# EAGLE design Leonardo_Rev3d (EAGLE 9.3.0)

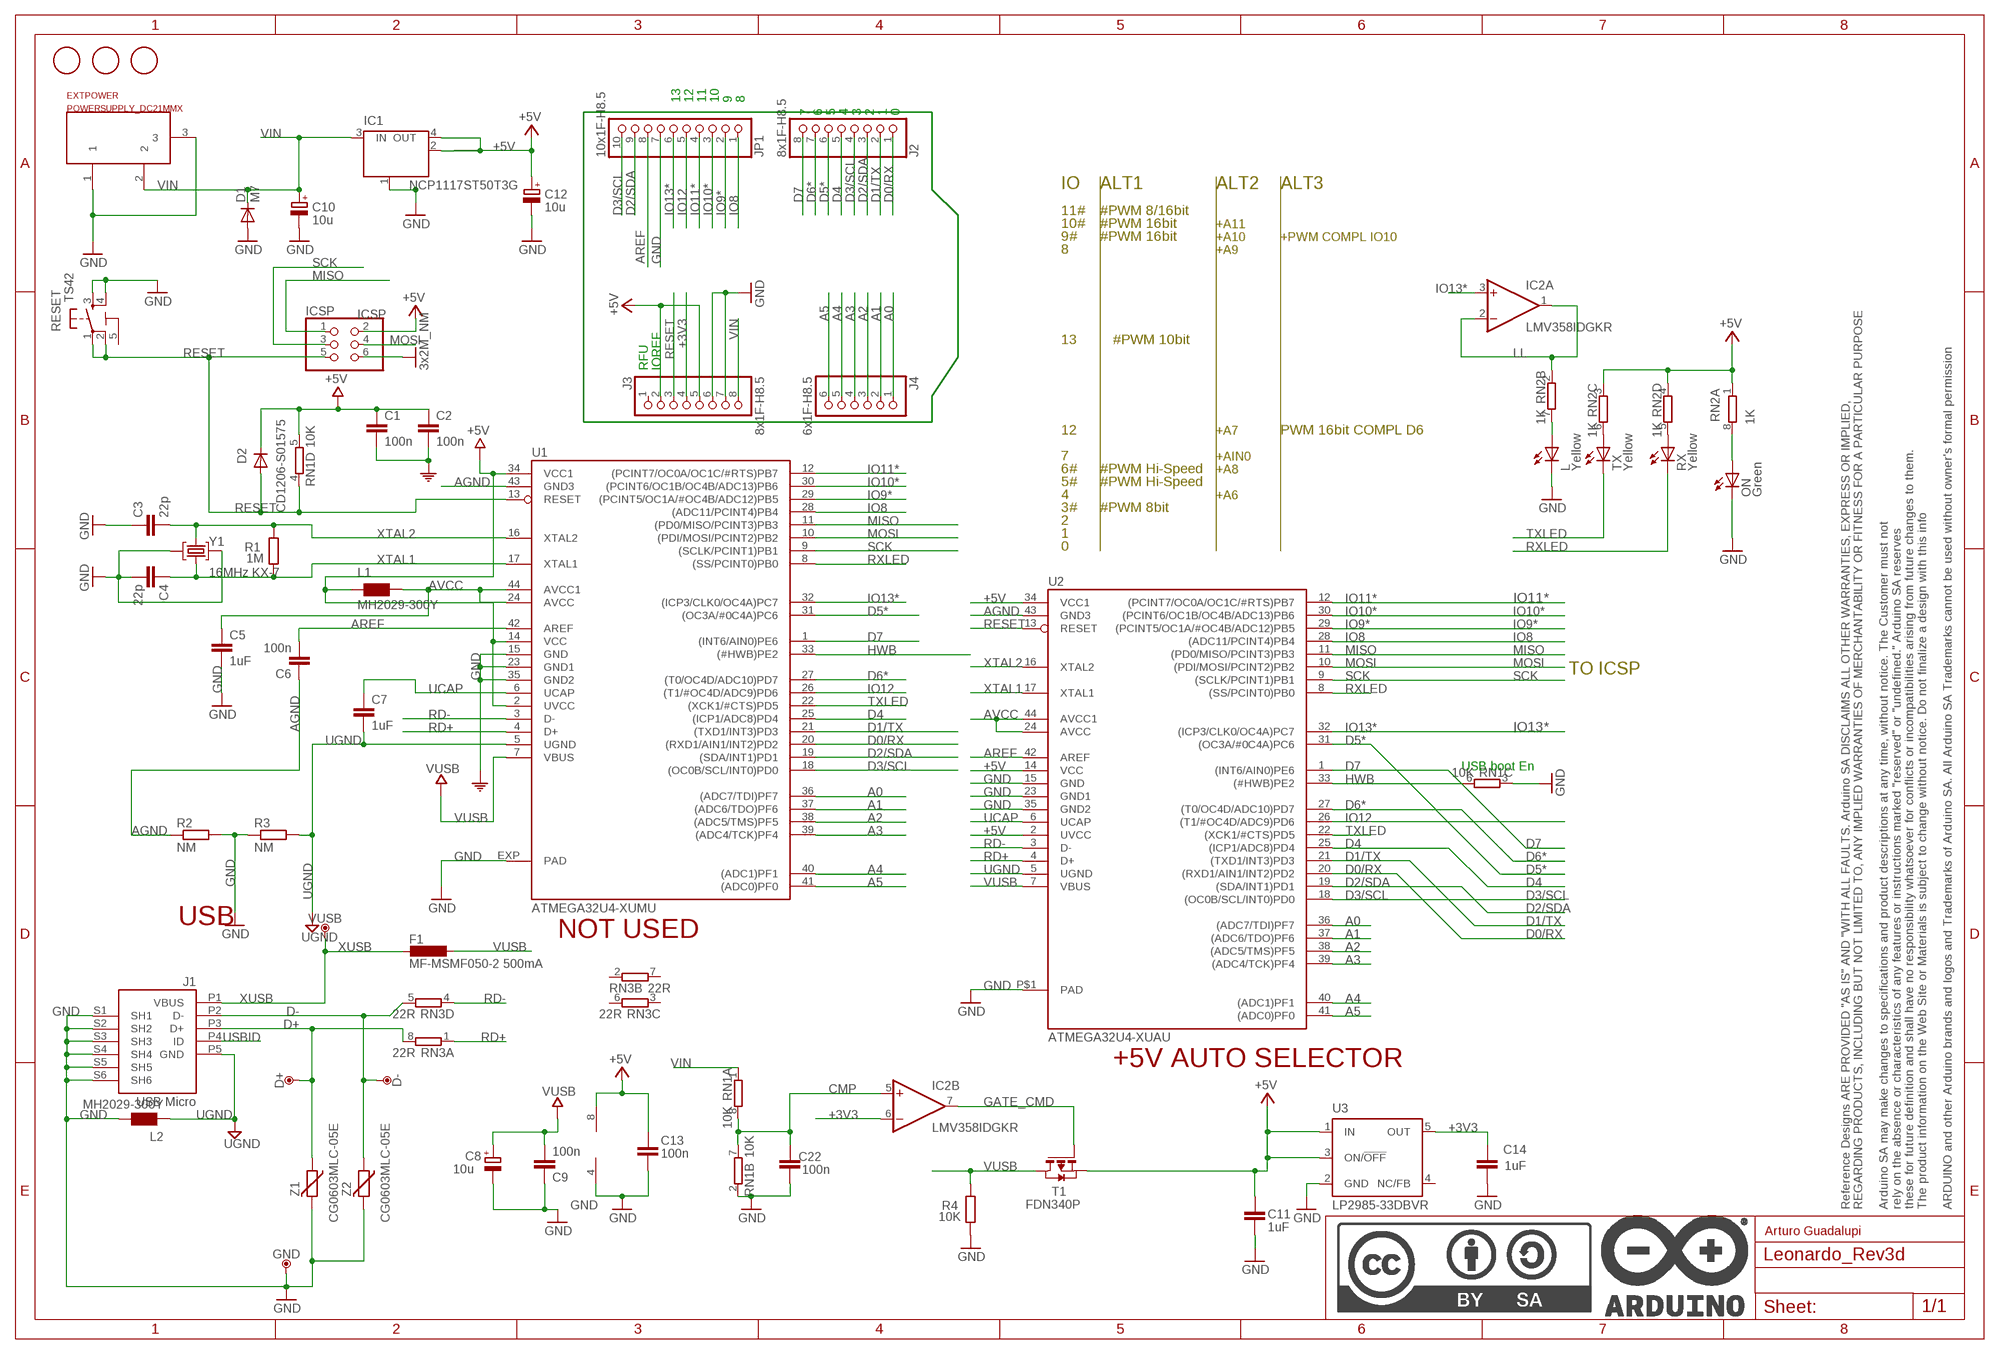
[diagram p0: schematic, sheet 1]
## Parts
C1  100n  C-EUC0603  [C0603-ROUND]
C2  100n  C-EUC0603  [C0603-ROUND]
C3  22p  C-EUC0603  [C0603-ROUND]
C4  22p  C-EUC0603  [C0603-ROUND]
C5  1uF  C-EUC0603  [C0603-ROUND]
C6  100n  C-EUC0603  [C0603-ROUND]
C7  1uF  C-EUC0603  [C0603-ROUND]
C8  10u  CPOL-EUSMCB  [SMC_B]
C9  100n  C-EUC0603  [C0603-ROUND]
C10  10u  CPOL-EUSMCB  [SMC_B]
C11  1uF  C-EUC0603  [C0603-ROUND]
C12  10u  CPOL-EUSMCB  [SMC_B]
C13  100n  C-EUC0603  [C0603-ROUND]
C14  1uF  C-EUC0603  [C0603-ROUND]
C22  100n  C-EUC0603  [C0603-ROUND]
D1  M7  DIODE-SMB  [SMB]
D2  CD1206-S01575  DIODE-MINIMELF  [MINIMELF]
D+  DNP  TPTP-1.00MM  [TP-1.00MM]
D-  DNP  TPTP-1.00MM  [TP-1.00MM]
EXTPOWER  POWERSUPPLY_DC21MMX  [POWERSUPPLY_DC-21MM]
F1  MF-MSMF050-2 500mA  L-EUL1812  [L1812]
FID1  DNP  FIDUCIAL-1.5MM  [FD-1-1.5]
FID2  DNP  FIDUCIAL-1.5MM  [FD-1-1.5]
FID3  DNP  FIDUCIAL-1.5MM  [FD-1-1.5]
FRAME1  DNP  A3-FRAME  [FRAME]
GND  DNP  TPTP-1.00MM  [TP-1.00MM]
IC1  NCP1117ST50T3G  MC33269ST-3.3T3  [SOT223]
IC2  LMV358IDGKR  LMV358MMX  [MSOP08]
ICSP  ICSP  PINHD-2X3  [2X03]
J1  USB Micro  USB-MICRO-LEGACY  [CON2_USB_MICRO_B_AT]
J2  8x1F-H8.5  PINHD-1X8  [1X08]
J3  8x1F-H8.5  PINHD-1X8  [1X08]
J4  6x1F-H8.5  PINHD-1X6  [1X06]
JP1  10x1F-H8.5  PINHD-1X10  [1X10]
L  Yellow  LEDCHIPLED_0805  [CHIPLED_0805]
L1  MH2029-300Y  WE-CBF_0805  [0805]
L2  MH2029-300Y  WE-CBF_0805  [0805]
ON  Green  LEDCHIPLED_0805  [CHIPLED_0805]
R1  1M  R-EU_R0603  [R0603-ROUND]
R2  NM  R-EU_R0402  [R0402]
R3  NM  R-EU_R0402  [R0402]
R4  10K  R-EU_R0603  [R0603-ROUND]
RESET  TS42  [TS42]
RN1  10K  4R-NCAY16  [CAY16]
RN2  1K  4R-NCAY16  [CAY16]
RN3  22R  4R-NCAY16  [CAY16]
RX  Yellow  LEDCHIPLED_0805  [CHIPLED_0805]
T1  FDN340P  PMOSSOT23  [SOT-23]
TX  Yellow  LEDCHIPLED_0805  [CHIPLED_0805]
U1  ATMEGA32U4-XUMU  [QFN44ML7X7]
U2  ATMEGA32U4-XUAU  [TQFP44-PAD]
U3  LP2985-33DBVR  LP2985-XXDBVR33  [SOT23-DBV]
VUSB  DNP  TPTP-1.00MM  [TP-1.00MM]
Y1  16MHz KX-7  CRYSTAL-3.2-2.5  [CRYSTAL-3.2-2.5]
Z1  CG0603MLC-05E  VARISTORCN0603  [CT/CN0603]
Z2  CG0603MLC-05E  VARISTORCN0603  [CT/CN0603]

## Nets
+3V3: C14.2 IC2.6(B:-IN) J3.4 U3.5(OUT)
+5V [usbvcc]: C1.1 C2.1 C11.2 C12.+ C13.1 D2.C IC1.2(OUT) IC1.4(OUT) IC2.8(P:V+) ICSP.2 J3.2 J3.5 L1.1 RN1.5 RN2.1 RN2.3 RN2.4 T1.2(S) U1.2(UVCC) U1.14(VCC) U1.34(VCC1) U2.2(UVCC) U2.14(VCC) U2.34(VCC1) U3.1(IN) U3.3(ON/!OFF)
A0: J4.1 U1.36((ADC7/TDI)PF7) U2.36((ADC7/TDI)PF7)
A1: J4.2 U1.37((ADC6/TDO)PF6) U2.37((ADC6/TDO)PF6)
A2: J4.3 U1.38((ADC5/TMS)PF5) U2.38((ADC5/TMS)PF5)
A3: J4.4 U1.39((ADC4/TCK)PF4) U2.39((ADC4/TCK)PF4)
A4: J4.5 U1.40((ADC1)PF1) U2.40((ADC1)PF1)
A5: J4.6 U1.41((ADC0)PF0) U2.41((ADC0)PF0)
AGND: C6.1 R2.1 U1.43(GND3) U2.43(GND3)
AREF [aref]: C6.2 JP1.8 U1.42(AREF) U2.42(AREF)
AVCC: C5.1 L1.2 U1.24(AVCC) U1.44(AVCC1) U2.24(AVCC) U2.44(AVCC1)
CMP: C22.2 IC2.5(B:+IN) RN1.7 RN1.8
D0/RX: J2.1 U1.20((RXD1/AIN1/INT2)PD2) U2.20((RXD1/AIN1/INT2)PD2)
D1/TX: J2.2 U1.21((TXD1/INT3)PD3) U2.21((TXD1/INT3)PD3)
D2/SDA: J2.3 JP1.9 U1.19((SDA/INT1)PD1) U2.19((SDA/INT1)PD1)
D3/SCL: J2.4 JP1.10 U1.18((OC0B/SCL/INT0)PD0) U2.18((OC0B/SCL/INT0)PD0)
D4: J2.5 U1.25((ICP1/ADC8)PD4) U2.25((ICP1/ADC8)PD4)
D5*: J2.6 U1.31((OC3A/#0C4A)PC6) U2.31((OC3A/#0C4A)PC6)
D6*: J2.7 U1.27((T0/OC4D/ADC10)PD7) U2.27((T0/OC4D/ADC10)PD7)
D7: J2.8 U1.1((INT6/AIN0)PE6) U2.1((INT6/AIN0)PE6)
D+: D+.X J1.P3(D+) RN3.8 Z1.1
D-: D-.X J1.P2(D-) RN3.5 Z2.1
GATE_CMD: IC2.7(B:OUT) T1.3(G)
GND [gnd]: C1.2 C2.2 C3.1 C4.2 C5.2 C8.- C9.1 C10.- C11.1 C12.- C13.2 C14.1 C22.1 D1.A EXTPOWER.1 EXTPOWER.3 GND.X IC1.1(GND/ADJ) IC2.4(P:V-) ICSP.6 J1.S1(SH1) J1.S2(SH2) J1.S3(SH3) J1.S4(SH4) J1.S5(SH5) J1.S6(SH6) J3.6 J3.7 JP1.7 L2.2 L.C ON.C R2.2 R3.1 R4.1 RESET.3 RESET.4 RN1.2 RN1.3 U1.15(GND) U1.23(GND1) U1.35(GND2) U1.EXP(PAD) U2.15(GND) U2.23(GND1) U2.35(GND2) U2.P$1(PAD) U3.2(GND) Y1.2(GND) Y1.4(GND) Z1.2 Z2.2 ; supply symbol labelled 3x2M_NM, COM
HWB: RN1.6 U1.33((#HWB)PE2) U2.33((#HWB)PE2)
IO8: JP1.1 U1.28((ADC11/PCINT4)PB4) U2.28((ADC11/PCINT4)PB4)
IO9*: JP1.2 U1.29((PCINT5/OC1A/#OC4B/ADC12)PB5) U2.29((PCINT5/OC1A/#OC4B/ADC12)PB5)
IO10*: JP1.3 U1.30((PCINT6/OC1B/OC4B/ADC13)PB6) U2.30((PCINT6/OC1B/OC4B/ADC13)PB6)
IO11*: JP1.4 U1.12((PCINT7/OC0A/OC1C/#RTS)PB7) U2.12((PCINT7/OC0A/OC1C/#RTS)PB7)
IO12: JP1.5 U1.26((T1/#OC4D/ADC9)PD6) U2.26((T1/#OC4D/ADC9)PD6)
IO13*: IC2.3(A:+IN) JP1.6 U1.32((ICP3/CLK0/OC4A)PC7) U2.32((ICP3/CLK0/OC4A)PC7)
LL: IC2.1(A:OUT) IC2.2(A:-IN) RN2.2
MISO: ICSP.1 U1.11((PD0/MISO/PCINT3)PB3) U2.11((PD0/MISO/PCINT3)PB3)
MOSI: ICSP.4 U1.10((PDI/MOSI/PCINT2)PB2) U2.10((PDI/MOSI/PCINT2)PB2)
N$2: L.A RN2.7
N$3: ON.A RN2.8
N$6: RN2.6 TX.A
N$8: RN2.5 RX.A
RD+: RN3.1 U1.4(D+) U2.4(D+)
RD-: RN3.4 U1.3(D-) U2.3(D-)
RESET: D2.A ICSP.5 J3.3 RESET.1 RESET.2 RN1.4 U1.13(RESET) U2.13(RESET)
RXLED: RX.C U1.8((SS/PCINT0)PB0) U2.8((SS/PCINT0)PB0)
SCK: ICSP.3 U1.9((SCLK/PCINT1)PB1) U2.9((SCLK/PCINT1)PB1)
TXLED: TX.C U1.22((XCK1/#CTS)PD5) U2.22((XCK1/#CTS)PD5)
UCAP: C7.1 U1.6(UCAP) U2.6(UCAP)
UGND [gnd]: C7.2 J1.P5(GND) L2.1 R3.2 U1.5(UGND) U2.5(UGND)
USBID: J1.P4(ID)
VIN [power]: C10.+ D1.C EXTPOWER.2 IC1.3(IN) J3.8 RN1.1
VUSB: C8.+ C9.2 F1.1 R4.2 T1.1(D) U1.7(VBUS) U2.7(VBUS)
XTAL1: C4.1 R1.1 U1.17(XTAL1) U2.17(XTAL1) Y1.1(C1)
XTAL2: C3.2 R1.2 U1.16(XTAL2) U2.16(XTAL2) Y1.3(C2)
XUSB [usbvcc]: F1.2 J1.P1(VBUS) VUSB.X
Unconnected: J3.1 RN3.2 RN3.3 RN3.6 RN3.7 U3.4(NC/FB)

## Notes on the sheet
- 13 | 12 | 11 | 10 | 9 | 8
- 7 | 6 | 5 | 4 | 3 | 2 | 1 | 0
- IO | ALT1 | ALT2 | ALT3
- 11# | #PWM 8/16bit
- 10# | #PWM 16bit | +A11
- 9# | #PWM 16bit | +A10 | +PWM COMPL IO10
- 8 | +A9
- 13 | #PWM 10bit
- RFU | IOREF
- 12 | +A7 | PWM 16bit COMPL D6
- 7 | +AIN0
- 6# | #PWM Hi-Speed | +A8
- 5# | #PWM Hi-Speed
- 4 | +A6
- 3# | #PWM 8bit
- 2
- 1
- 0
- TO ICSP
- USB boot En
- USB
- NOT USED
- +5V AUTO SELECTOR
- Arturo Guadalupi

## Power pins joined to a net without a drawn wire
5-GND: RESET.5(5-GND)

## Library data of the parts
C1-C7 C9 C11 C13 C14 C22 = SmartPrj:C-EU: CAPACITOR, European symbol
C8 C10 C12 = rcl:CPOL-EU: POLARIZED CAPACITOR, European symbol
D1 D2 = diode:DIODE-: DIODE
D+ D- GND VUSB = Arduino-utility:TP: Testpoint; DATASHEET: DNP; DISTRIBUTOR-LINK: DNP; DISTRIBUTOR-PN: DNP; MANUFACTURER: DNP; MANUFACTURER-PN: DNP
EXTPOWER = SmartPrj:POWERSUPPLY_DC21MM
F1 = rcl:L-EU: INDUCTOR, European symbol
FID1-FID3 = Arduino-utility:FIDUCIAL: Fiducial mount; DATASHEET: DNP; DISTRIBUTOR-LINK: DNP; DISTRIBUTOR-PN: DNP; MANUFACTURER: DNP; MANUFACTURER-PN: DNP
FRAME1 = Arduino-utility:A3-FRAME; CODE-ARDUINO: DNP; DATASHEET: DNP; DISTRIBUTOR-LINK: DNP; DISTRIBUTOR-PN: DNP; MANUFACTURER: DNP; MANUFACTURER-PN: DNP; NOTE: DNP
IC1 = linear:MC33269ST*: Adjustable Output Low Dropout Voltage Regulator 800 mA Source: http://www.onsemi.com/pub/Collateral/MC33269-D.PDF
IC2 = linear:LMV358?*: Dual General Purpose, Low Voltage, Rail-to-Rail Output Operational Amplifiers Source: http://www.national.com/mpf/LM/LMV321.html http://www.national.com/dt/lmv_qual.pdf
ICSP = SmartPrj:PINHD-2X3: PIN HEADER
J1 = Arduino-connectors:USB-MICRO-LEGACY; DATASHEET: http://media.digikey.com/pdf/Data%20Sheets/FCI%20PDFs/10118193-0001LF_Webpage.PDF; DISTRIBUTOR-LINK: http://www.digikey.it/product-detail/en/10118193-0001LF/609-4616-2-ND/2785388; DISTRIBUTOR-PN: 609-4616-2-ND; MANUFACTURER: FCI; MANUFACTURER-PN: 10118193-0001LF
J2 J3 = SmartPrj:PINHD-1X8: PIN HEADER
J4 = SmartPrj:PINHD-1X6: PIN HEADER
JP1 = SmartPrj:PINHD-1X10: PIN HEADER
L ON RX TX = led:LED: LED
L1 L2 = wuerth-elektronik:WE-CBF: SMD EMI Suppression Ferrite Beads
R1-R4 = SmartPrj:R-EU_: RESISTOR, European symbol
RESET = SmartPrj:TS42: TS42 Dongnan Electronics Tact switch VDC 12V - 50mA
RN1-RN3 = resistor-dil:4R-N: Array Chip Resistor Source: RS Component / Phycomp
T1 = zetex:PMOSSOT23: MOS FET
U1 U2 = SmartPrj:ATMEGA32U4-XU
U3 = SmartPrj:LP2985-XXDBVR: ULTRALOW-POWER 50-mA LOW-DROPOUT LINEAR REGULATORS 50-mA Low-Dropout Regulator Source: http://focus.ti.com/lit/ds/symlink/tps77001.pdf
Y1 = SmartPrj:CRYSTAL-3.2-2.5
Z1 Z2 = varistor:VARISTOR: VARISTOR

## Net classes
0 default: width 0.254 mm, drill 0.499 mm, clearance 0.254 mm
1 power: width 0.254 mm, drill 0.499 mm, clearance 0.254 mm
2 gnd: width 0.254 mm, drill 0.499 mm, clearance 0.254 mm
3 usbvcc: width 0.254 mm, drill 0.499 mm, clearance 0.254 mm
4 aref: width 0.254 mm, drill 0.499 mm, clearance 0.254 mm

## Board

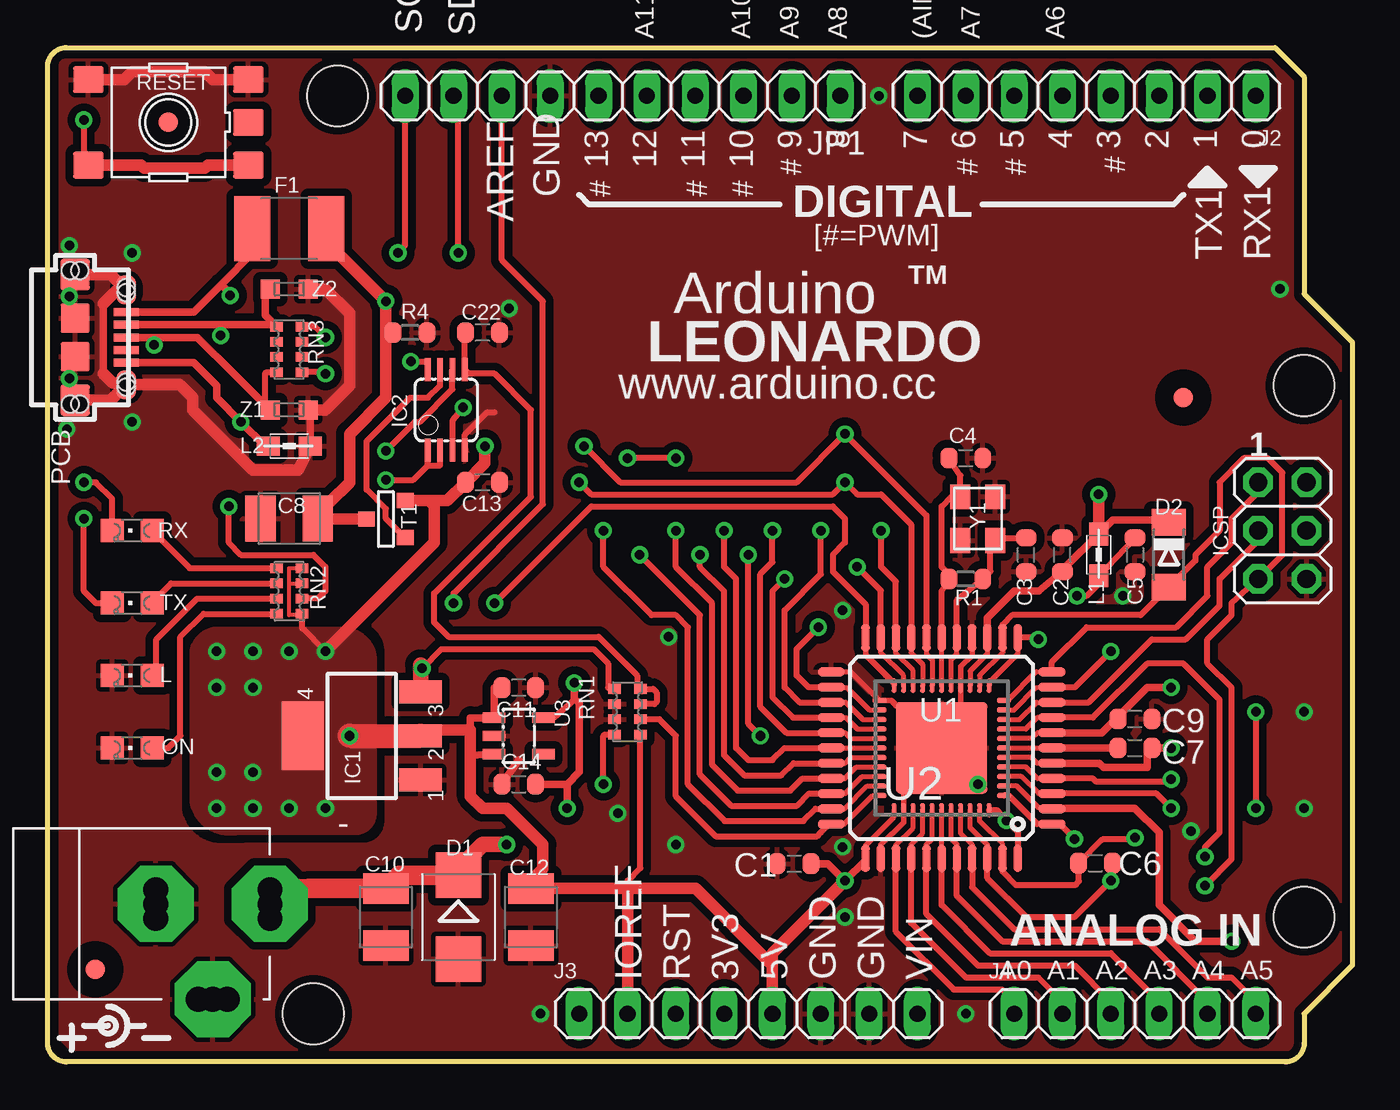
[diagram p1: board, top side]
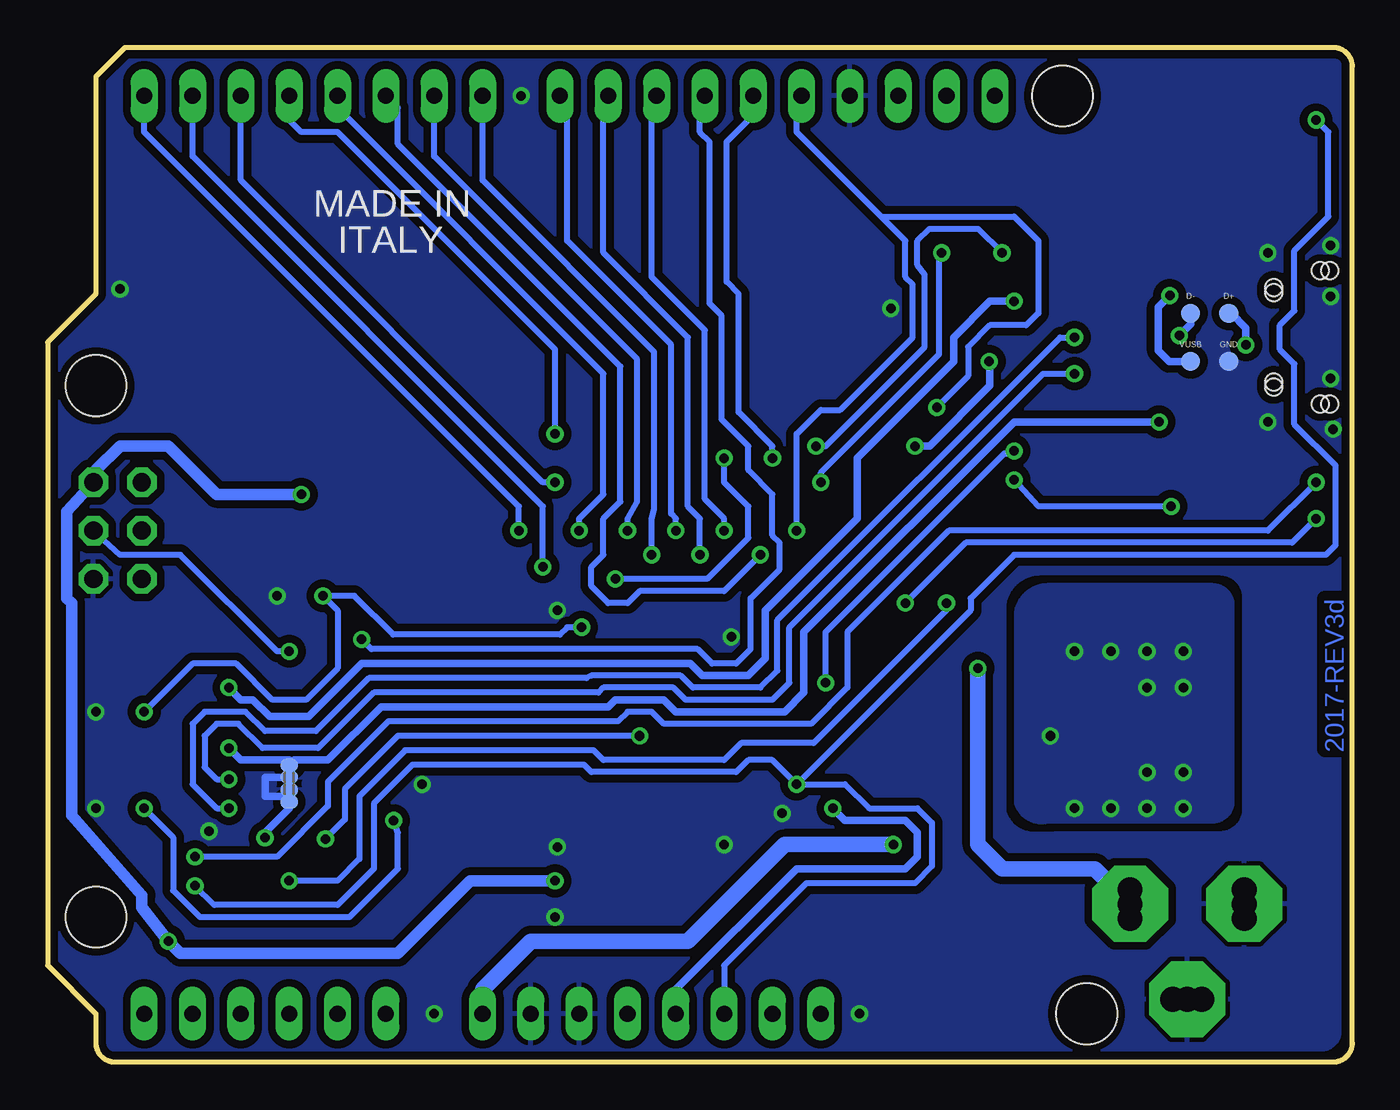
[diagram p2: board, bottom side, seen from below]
Size 68.58 x 53.34 mm. Coordinates in mm from the lower left corner, seen from the top.
Outline: 64.52,53.34 66.04,51.82 66.04,40.39 68.58,37.85 68.58,5.08 66.04,2.54 66.04,1 arc-90 65.04,0 1,0 arc-90 0,1 0,52.34 arc-90 1,53.34 64.52,53.34
Copper layers (1*16): Top 0.035mm / dielectric 1.5mm / Bottom 0.035mm
Design rules "SeeedStudio_2layers *": minimum track width 6mil, minimum drill 0.499mm, track to track 6mil, track to pad 6mil, pad to pad 6mil, via to via 6mil, smd to smd 0mil, copper to edge 10mil, drill to drill 10mil, minimum pad ring 10mil, minimum via ring 6mil, stop-mask expansion 2mil, vias tented up to drill 100mil, thermal gap 10mil
Holes 3.2 mm at 66.04,35.56 66.04,7.62 15.24,50.8 13.97,2.54
vRestrict: area 42.5,38.6 to 43.1,38.9; area 35.8,35.2 to 36.4,35.7; area 44.5,35.2 to 45.2,35.7; area 41.3,35.2 to 41.8,35.7; area 47.9,10.3 to 48.5,10.8; area 50.4,10.2 to 50.9,11

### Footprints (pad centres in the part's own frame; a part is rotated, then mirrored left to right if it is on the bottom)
C0603-ROUND = smd 0.898 x 1.1: 1 -0.889,0; 2 0.889,0
SMC_B = smd 1.6 x 2.4: + -1.5,0; - 1.5,0
SMB = smd 2.4 x 2.4: A 2.2,0; C -2.2,0
MINIMELF = smd 1.4 x 1.8: A 1.7,0; C -1.7,0
TP-1.00MM = smd 1 x 1 bottom: X 0,0
POWERSUPPLY_DC-21MM = drill 1.3 pad 4 octagon: 1 -5.08,-3.353; 2 -0.076,-6.35; 3 -0.076,-0.356 | drill 1.3: 4 -5.08,-4.115; 5 -5.08,-2.591; 6 -0.838,-0.356; 7 0.686,-0.356; 8 -0.838,-6.35; 9 0.686,-6.35
L1812 = smd 1.9 x 3.4: 1 -1.95,0; 2 1.95,0
FD-1-1.5 = smd 1.016 x 1.016: P$1 0,0
SOT223 = smd 1.219 x 2.235: 1 -2.311,-3.099; 2 0,-3.099; 3 2.311,-3.099 | smd 3.6 x 2.2: 4 0,3.099
MSOP08 = smd 0.3 x 1.2: 1 -0.976,-2.113; 2 -0.326,-2.113; 3 0.324,-2.113; 4 0.974,-2.113; 5 0.974,2.112; 6 0.324,2.112; 7 -0.326,2.112; 8 -0.976,2.112
2X03 = drill 0.95 pad 1.55 octagon: 1 -2.54,-1.27; 2 -2.54,1.27; 3 0,-1.27; 4 0,1.27; 5 2.54,-1.27; 6 2.54,1.27
CON2_USB_MICRO_B_AT = smd 0.406 x 1.346: P1 -1.321,2.692; P2 -0.66,2.692; P3 0,2.692; P4 0.66,2.692; P5 1.321,2.692 | smd 1.651 x 1.549: S1 -3.302,0; S2 3.302,0 | smd 1.524 x 1.016: S3 -2.489,2.692; S4 2.489,2.692 | smd 1.524 x 1.524: S5 -1.016,0; S6 1.016,0 | hole 0.9: -3.505,0.254; -3.505,-0.254; 3.505,0.254; 3.505,-0.254; -2.616,2.692; -2.362,2.692; 2.362,2.692; 2.616,2.692
1X08 = drill 0.85 pad 1.422 long: 1 -8.89,0; 2 -6.35,0; 3 -3.81,0; 4 -1.27,0; 5 1.27,0; 6 3.81,0; 7 6.35,0; 8 8.89,0
1X06 = drill 0.85 pad 1.422 long: 1 -6.35,0; 2 -3.81,0; 3 -1.27,0; 4 1.27,0; 5 3.81,0; 6 6.35,0
1X10 = drill 0.85 pad 1.422 long: 1 -11.43,0; 2 -8.89,0; 3 -6.35,0; 4 -3.81,0; 5 -1.27,0; 6 1.27,0; 7 3.81,0; 8 6.35,0; 9 8.89,0; 10 11.43,0
CHIPLED_0805 = smd 1.2 x 1.2: A 0,-1.05; C 0,1.05
0805 = smd 1.2 x 1: 1 -1.1,0; 2 1.1,0
R0603-ROUND = smd 0.898 x 1.1: 1 -0.889,0; 2 0.889,0
R0402 = smd 0.7 x 0.9: 1 -0.65,0; 2 0.65,0
TS42 = smd 1.6 x 1.4: 1 -4.2,2.25; 2 4.2,2.25; 3 -4.2,-2.25; 4 4.2,-2.25; 5 -4.2,0
CAY16 = smd 0.5 x 0.65: 1 -1.2,-0.675; 2 -0.4,-0.675; 3 0.4,-0.675; 4 1.2,-0.675; 5 1.2,0.675; 6 0.4,0.675; 7 -0.4,0.675; 8 -1.2,0.675
SOT-23 = smd 0.787 x 0.889: 1 0.025,-1.016; 2 -0.94,1.016; 3 0.991,1.016
QFN44ML7X7 = smd 0.75 x 0.275: 1 -3.275,2.5; 2 -3.275,2; 3 -3.275,1.5; 4 -3.275,1; 5 -3.275,0.5; 6 -3.275,0; 7 -3.275,-0.5; 8 -3.275,-1; 9 -3.275,-1.5; 10 -3.275,-2; 11 -3.275,-2.5; 23 3.275,-2.5; 24 3.275,-2; 25 3.275,-1.5; 26 3.275,-1; 27 3.275,-0.5; 28 3.275,0; 29 3.275,0.5; 30 3.275,1; 31 3.275,1.5; 32 3.275,2; 33 3.275,2.5 | smd 0.275 x 0.75: 12 -2.5,-3.275; 13 -2,-3.275; 14 -1.5,-3.275; 15 -1,-3.275; 16 -0.5,-3.275; 17 0,-3.275; 18 0.5,-3.275; 19 1,-3.275; 20 1.5,-3.275; 21 2,-3.275; 22 2.5,-3.275; 34 2.5,3.275; 35 2,3.275; 36 1.5,3.275; 37 1,3.275; 38 0.5,3.275; 39 0,3.275; 40 -0.5,3.275; 41 -1,3.275; 42 -1.5,3.275; 43 -2,3.275; 44 -2.5,3.275 | smd 4.826 x 4.826: EXP 0,0
TQFP44-PAD = smd 1.4 x 0.45: 1 -5.8,4; 2 -5.8,3.2; 3 -5.8,2.4; 4 -5.8,1.6; 5 -5.8,0.8; 6 -5.8,0; 7 -5.8,-0.8; 8 -5.8,-1.6; 9 -5.8,-2.4; 10 -5.8,-3.2; 11 -5.8,-4; 23 5.8,-4; 24 5.8,-3.2; 25 5.8,-2.4; 26 5.8,-1.6; 27 5.8,-0.8; 28 5.8,0; 29 5.8,0.8; 30 5.8,1.6; 31 5.8,2.4; 32 5.8,3.2; 33 5.8,4 | smd 0.45 x 1.4: 12 -4,-5.8; 13 -3.2,-5.8; 14 -2.4,-5.8; 15 -1.6,-5.8; 16 -0.8,-5.8; 17 0,-5.8; 18 0.8,-5.8; 19 1.6,-5.8; 20 2.4,-5.8; 21 3.2,-5.8; 22 4,-5.8; 34 4,5.8; 35 3.2,5.8; 36 2.4,5.8; 37 1.6,5.8; 38 0.8,5.8; 39 0,5.8; 40 -0.8,5.8; 41 -1.6,5.8; 42 -2.4,5.8; 43 -3.2,5.8; 44 -4,5.8 | smd 1 x 1: P$1 0,0
SOT23-DBV = smd 0.55 x 1.2: 1 -0.95,-1.3; 2 0,-1.3; 3 0.95,-1.3; 4 0.95,1.3; 5 -0.95,1.3
CRYSTAL-3.2-2.5 = smd 1.3 x 1.05: 1 -1.15,-0.925; 2 1.15,-0.925; 3 1.15,0.925; 4 -1.15,0.925
CT/CN0603 = smd 1 x 1: 1 -1,0; 2 1,0

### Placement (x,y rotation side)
C1  39.23,10.43 180 top
C2  53.34,26.67 90 top
C3  51.44,26.67 90 top
C4  48.26,31.75 0 top
C5  57.15,26.67 270 top
C6  55.08,10.45 0 top
C7  57.15,16.51 0 top
C8  12.7,28.57 180 top
C9  57.15,18.03 180 top
C10  17.78,7.62 270 top
C11  24.77,19.68 180 top
C12  25.4,7.62 270 top
C13  22.86,30.48 0 top
C14  24.77,14.61 0 top
C22  22.86,38.35 180 top
D1  21.59,7.62 270 top
D2  58.93,26.67 270 top
D+  6.5,39.37 0 top
D-  8.51,39.37 0 top
EXTPOWER  5.33,8.38 90 top
F1  12.7,43.81 180 top
FID1  6.35,49.4 0 top
FID2  59.69,34.92 0 top
FID3  2.5,4.88 0 top
FRAME1  0,0 0 top
GND  6.5,36.83 0 top
IC1  16.51,17.14 90 top
IC2  20.95,34.29 0 top
ICSP  64.9,27.94 270 top
J1  1.45,38.1 270 top
J2  54.61,50.8 180 top
J3  36.83,2.54 0 top
J4  57.15,2.54 0 top
JP1  30.23,50.8 180 top
L  4.45,20.32 90 top
L1  55.24,26.67 270 top
L2  12.7,32.38 0 top
ON  4.45,16.51 90 top
R1  48.26,25.4 0 top
R2  55.88,14.33 90 bottom
R3  55.88,14.96 90 bottom
R4  19.05,38.35 180 top
RESET  6.35,49.4 180 top
RN1  30.48,18.41 270 top
RN2  12.7,24.77 90 top
RN3  12.7,37.47 90 top
RX  4.45,27.94 90 top
T1  17.78,28.57 270 top
TX  4.45,24.13 90 top
U1  46.99,16.51 180 top
U2  46.99,16.51 180 top
U3  24.77,17.14 270 top
VUSB  8.51,36.83 0 top
Y1  48.9,28.57 270 top
Z1  12.7,34.29 0 top
Z2  12.7,40.64 0 top

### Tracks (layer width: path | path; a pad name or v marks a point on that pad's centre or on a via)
+3V3  (via drill 0.5 pad 0.9)
  Top 0.305: IC2.6 21.28,35.38 19.56,33.66 19.3,33.66 v17.78,32.13 | U3.5 26.6,18.09 27.69,19.05
  Top 0.406: 27.3,14.61 C14.2 | 27.3,14.61 27.94,15.24 27.94,18.92 27.69,19.05 v27.69,19.94 | v27.3,13.34 27.3,14.61
  Bottom 0.305: v17.78,32.13 17.91,32.13 18.03,32 18.29,32 27.69,22.61 v27.69,19.94
  Bottom 0.406: J3.4 35.56,3.81 29.21,10.16 23.5,10.16 22.86,10.79 22.86,12.06 23.5,12.7 26.67,12.7 v27.3,13.34
+5V  (via drill 0.5 pad 0.9)
  Top 0.203: 12.7,25.16 12.7,23.5 13.3,23.5 | 12.7,25.16 RN2.3 | 12.7,25.16 12.7,25.96 RN2.4
  Top 0.254: U1.2 50.95,14.51 52.12,13.34 52.77,13.34 | U1.14 48.49,20.55 49.39,21.45 U2.14 | U1.34 44.49,12.89 42.99,11.39 U2.34
  Top 0.305: v14.61,21.59 13.38,22.82 RN2.1 13.3,23.5 | IC2.8 19.98,36.83 v19.09,36.83 | 52.77,13.34 U2.2 | RN1.5 31.16,10.2 30.48,9.53 30.48,9.12
  Top 0.406: 22.23,16.13 U3.3 | 22.23,17.46 22.23,18.09 U3.1 23.46,19.67 C11.2 | U2.14 49.39,23.36 50.8,24.77 52.09,24.77 C2.1 53.49,26.02 L1.1 55.97,28.5 58.75,28.5 58.8,28.45 D2.C | v62.23,6.35 60.33,6.35 58.42,8.26 58.42,12.06 57.15,13.34 52.77,13.34 | U2.34 42.99,10.61 v41.91,9.53 41.01,10.43 C1.1 | 25,9.12 C12.+
  Top 0.61: IC1.2 19.93,17.46 22.23,17.46 22.23,16.13 22.23,13.97 22.86,13.34 24.13,13.34 26.04,11.43 26.04,10.16 25,9.12 | 20.07,29.52 20.32,29.26 20.32,27.3 v14.61,21.59 | 20.07,29.52 T1.2 | C12.+ 30.48,9.12 | 38.1,5.08 34.06,9.12 30.48,9.12 | 38.1,5.08 J3.5 | 30.48,9.12 J3.2 | v55.24,29.84 L1.1 | 38.1,5.08 38.1,5.71 v41.91,9.53 | v22.99,32.38 22.99,31.5 C13.1 21.01,29.52 20.07,29.52
  Top 1.27: v15.88,17.14 IC1.2
  Bottom 0.406: v22.99,32.38 22.23,32.38 19.05,35.56 19.05,36.54 v19.09,36.83
  Bottom 0.61: v55.24,29.84 59.69,29.84 62.23,32.38 64.77,32.38 66.04,31.11 ICSP.2 67.56,28.96 67.56,24.38 67.31,24.13 67.31,12.95 63.63,8.76 63.63,8.13 v62.23,6.35 61.59,5.71 50.16,5.71 46.35,9.53 v41.91,9.53
  other vias: 8.89,21.59 14.61,13.34 10.79,21.59 12.7,21.59 8.89,13.34 10.79,13.34 12.7,13.34 8.89,19.69 8.89,15.23 10.79,15.23 10.79,19.69
  pour Top (no thermals): 7.62,21.61 arc-90 9.26,22.73 15.51,22.73 arc-90 17.14,21.1 17.14,13.06 arc-90 16.14,12.06 9.89,12.06 arc-90 7.62,13.7
  pour Bottom (isolate 0.406, no thermals): 16.02,25.02 arc-90 17.65,23.38 17.65,13.7 arc-90 16.02,12.7 7.35,12.7 arc-90 6.35,13.7 6.35,24.02 arc-90 7.35,25.02
A0
  Top 0.254: U1.36 45.49,12.32 44.59,11.42 U2.36
  Top 0.305: U2.36 44.59,6.84 47.62,3.81 50.16,3.81 50.8,3.17 J4.1
A1
  Top 0.254: U2.37 45.39,11.43 45.99,12.03 U1.37
  Top 0.305: U2.37 45.39,7.32 48.26,4.45 52.07,4.45 53.34,3.17 J4.2
A2
  Top 0.254: U1.38 46.49,11.74 46.19,11.44 U2.38
  Top 0.305: U2.38 46.19,7.79 48.9,5.08 53.98,5.08 55.88,3.17 J4.3
A3
  Top 0.254: U2.39 U1.39
  Top 0.305: U2.39 46.99,8.26 49.53,5.71 55.88,5.71 58.42,3.17 J4.4
A4
  Top 0.254: U1.40 47.49,11.74 47.79,11.44 U2.40
  Top 0.305: U2.40 47.79,8.72 50.16,6.35 57.78,6.35 60.96,3.17 J4.5
A5
  Top 0.254: U1.41 47.99,12.03 48.59,11.43 U2.41
  Top 0.305: U2.41 48.59,9.2 50.8,6.99 58.42,6.99 60.96,4.45 62.23,4.45 63.5,3.17 J4.6
AGND  (via drill 0.5 pad 0.9)
  Top 0.254: U1.43 48.99,12.66 50.19,11.46 U2.43
  Top 0.305: U2.43 50.19,10.01 50.9,9.3 54,9.3 54.2,9.5 54.2,10.44 C6.1 | C6.1 53.95,10.35 | v57.15,11.79 57.06,11.7 55.44,11.7 C6.1
  Bottom 0.406: v57.15,11.79 57.15,12.06 55.88,13.34 R2.1
AREF  (via drill 0.5 pad 0.9)
  Top 0.254: U1.42 48.49,12.32 49.39,11.42 U2.42
  Top 0.305: U2.42 49.39,9.66 51.44,7.62 53.98,7.62 v55.88,9.53 55.88,10.37 C6.2 | JP1.8 23.88,42.16 26.04,40.01 26.04,29.34 21.34,24.64 v21.34,24.13
  Bottom 0.305: v21.34,24.13 21.34,23.75 28.32,16.76 32.13,16.76 33.02,15.88 39.37,15.88 39.88,16.38 49.78,16.38 52.2,13.97 52.2,10.67 53.34,9.53 v55.88,9.53
AVCC  (via drill 0.5 pad 0.9)
  Top 0.254: U2.24 41.22,19.68 42.01,19.68 43.18,18.52 43.57,18.52 U1.24
  Top 0.305: U2.44 50.99,12.1 v50.39,12.7 49.91,13.23 U1.44 | U2.24 39.98,19.71 39.37,20.32 39.37,21.72 v40.51,22.86 | v54.1,24.51 54.61,24.51 55.24,25.15 L1.2 55.7,26.02 C5.1 | v63.5,18.41 v63.5,13.34
  Bottom 0.305: v50.39,12.7 50.16,12.06 50.16,10.16 52.7,7.62 60.58,7.62 61.98,9.02 61.98,11.81 v63.5,13.34 | v63.5,18.41 60.96,20.95 58.67,20.95 56.77,19.05 54.99,19.05 53.34,20.7 53.34,23.75 v54.1,24.51 52.45,24.51 50.42,22.48 41.66,22.48 41.27,22.86 v40.51,22.86
CMP
  Top 0.305: RN1.8 31.05,19.61 | RN1.8 30.99,19.78 30.99,20.32 28.96,22.35 21.08,22.35 20.32,23.11 20.32,24.64 25.4,29.72 25.4,34.29 23.5,36.2 22.14,36.2 IC2.5 21.93,37.93 21.97,37.97 C22.2 | RN1.8 31.82,19.61 32,19.43 32,18.92 31.9,18.82 RN1.7
D0/RX  (via drill 0.5 pad 0.9)
  Top 0.254: U1.20 45.49,20.57 44.59,21.48 U2.20
  Top 0.305: U2.20 44.59,25.26 43.81,26.04 v43.81,27.94
  Bottom 0.305: v43.81,27.94 43.81,29.21 63.5,48.9 J2.1
D1/TX  (via drill 0.5 pad 0.9)
  Top 0.254: U1.21 44.99,20.31 43.79,21.51 U2.21
  Top 0.305: U2.21 43.79,24.79 v42.55,26.04
  Bottom 0.305: v42.55,26.04 42.55,29.21 60.96,47.62 J2.2
D2/SDA  (via drill 0.5 pad 0.9)
  Top 0.254: U1.19 45.99,20.91 45.39,21.51 U2.19
  Top 0.305: U2.19 45.39,28.27 43.81,29.84 42.55,29.84 v41.91,30.48 41.27,29.84 28.57,29.84 v27.94,30.48 | JP1.9 21.59,50.55 v21.59,42.55
  Bottom 0.305: v21.59,42.55 21.59,42.42 21.72,42.29 21.72,37.21 27.94,30.99 v27.94,30.48 | v41.91,30.48 42.55,30.48 58.42,46.35 J2.3
D3/SCL  (via drill 0.5 pad 0.9)
  Top 0.254: U1.18 46.49,21.15 46.19,21.45 U2.18
  Top 0.305: v18.41,42.55 18.8,42.93 JP1.10 | v28.19,32.38 30.1,30.48 39.37,30.48 v41.91,33.02 46.19,28.74 U2.18
  Bottom 0.305: v18.41,42.55 19.68,43.81 22.23,43.81 22.86,43.18 22.86,41.91 22.48,41.4 22.48,37.59 27.69,32.38 v28.19,32.38 | v41.91,33.02 41.91,37.47 53.34,48.9 55.24,48.9 55.88,49.53 J2.4
D4  (via drill 0.5 pad 0.9)
  Top 0.254: U2.25 41.95,18.91 42.85,18.01 U1.25
  Top 0.305: U2.25 39.51,18.91 38.73,19.68 38.73,23.75 40.64,25.65 v40.64,27.94
  Bottom 0.305: J2.5 53.34,50.16 39.37,36.2 39.37,29.84 40.64,28.57 v40.64,27.94
D5*  (via drill 0.5 pad 0.9)
  Top 0.254: U1.31 42.82,15.01 41.92,14.11 U2.31
  Top 0.305: U2.31 40.02,14.11 39.38,13.47 35.93,13.47 34.29,15.11 34.29,23.5 v31.11,26.67
  Bottom 0.305: J2.6 50.16,50.16 50.16,48.26 38.48,36.58 38.48,29.46 39.37,28.57 39.37,26.67 40.01,26.04 40.01,25.02 39.12,24.13 38.1,24.13 37.47,24.77 33.02,24.77 v31.11,26.67
D6*  (via drill 0.5 pad 0.9)
  Top 0.254: U2.27 41.92,17.31 42.22,17.01 U1.27
  Top 0.305: U2.27 38.82,17.31 37.47,18.67 37.47,25.65 38.1,26.29 v38.1,27.94
  Bottom 0.305: J2.7 48.26,47.62 37.59,36.96 37.59,29.46 38.1,28.57 v38.1,27.94
D7  (via drill 0.5 pad 0.9)
  Top 0.305: U1.1 50.51,14.01 52.01,12.51 U2.1 53.2,12.51 v53.98,11.73 | v37.47,17.14 36.83,17.78 v36.83,26.67
  Bottom 0.305: J2.8 45.72,46.35 36.7,37.34 36.7,29.08 36.83,28.57 v36.83,26.67 | v37.47,17.14 50.16,17.14 52.96,14.35 52.96,12.75 v53.98,11.73
D+  (via drill 0.5 pad 0.9)
  Top 0.305: RN3.8 11.5,36.27 11.43,36.2 11.43,34.66 Z1.1
  Top 0.406: J1.P3 5.6,38.1 | 5.6,38.1 7.87,38.1 9.78,36.2 9.79,36.2 Z1.1 | v5.6,37.7 5.6,38.1
  Bottom 0.406: D+.X 6.37,39.37 5.6,38.6 v5.6,37.7
D-  (via drill 0.5 pad 0.9)
  Top 0.305: Z2.1 11.43,40.27
  Top 0.406: J1.P2 9.1,38.76 | 9.1,38.76 11.93,38.76 RN3.5 11.43,39.26 11.43,40.27 | v9.1,38.2 9.1,38.76
  Bottom 0.406: D-.X 8.51,38.79 v9.1,38.2
GATE_CMD
  Top 0.305: IC2.7 20.63,35.56 19.99,34.92 19.05,34.92 16.76,32.64 16.76,30.1 17.78,29.08 17.78,28.57 18.77,27.58 T1.3
GND  (via drill 0.5 pad 0.9)
  Top 0.254: U1.23 42.22,20.51 U2.23
  Top 0.279: U2.15 48.59,21.39 47.99,20.79 U1.15 47.99,17.51 | 44.99,14.51 U1.35 44.99,12.61 43.79,11.4 U2.35 | 44.34,19.01 U1.23
  Top 0.305: U2.P$1 47.99,17.51 | 44.99,14.51 U2.P$1 | 44.34,19.01 44.6,18.75 44.76,18.75 U2.P$1 | U2.P$1 v48.9,14.61 | IC2.4 21.93,32.98 23.11,34.16 23.5,34.16 | J1.S4 4.06,35.69
  Top 0.406: C14.1 24.77,15.89 | L2.2 13.8,34.19 Z1.2 | 2.92,36.2 2.92,39.88
  Top 0.61: RESET.4 4.03,51.65 4.45,52.07 8.26,52.07 8.67,51.65 RESET.3 | L2.2 13.16,31.11 10.79,31.11 7.62,34.29 7.62,34.92 6.93,35.61 J1.S4 3.33,34.8 J1.S2 | Z2.2 14.61,40.64 15.88,39.37 15.88,35.56 14.61,34.29 Z1.2 | J1.S1 3.33,41.4 J1.S3 3.63,40.59 2.92,39.88 | 2.92,36.2 3.43,35.69 4.06,35.69
  Bottom 0.406: R3.1 R2.2 57.15,14.98 57.15,13.97 55.88,13.97 R3.1
  other vias: 41.78,11.3 60.1,12.14 41.78,23.75 56.52,24.51 24.26,39.62 33.02,11.43 29.97,13.08 41.91,7.62 66.04,13.34 66.04,18.41 48.26,2.54 43.69,50.8 32.64,22.35 4.45,42.55 4.45,33.66 25.91,2.54 1.14,40.26 1.14,35.94 1.14,42.93 1.02,33.27 64.77,40.64
  pour Bottom (isolate 0.406, rank 2): 0.64,52.7 69.22,52.7 69.22,0.64 1.64,0.64 arc-90 0.64,1.64
  pour Top (isolate 0.406, rank 2): 0.64,52.7 71.12,52.7 71.12,1.64 arc-90 70.12,0.64 1.64,0.64 arc-90 0.64,1.64
HWB
  Top 0.254: U1.33 43.37,14.01 41.87,12.51 U2.33
  Top 0.305: U2.33 41.09,12.51 40.64,12.06 40.45,11.88 35.12,11.88 33.02,13.97 33.02,17.14 32.15,18.02 RN1.6
IO8  (via drill 0.5 pad 0.9)
  Top 0.254: U2.28 U1.28
  Top 0.305: U2.28 38.73,16.51 38.1,15.88 36.83,15.88 36.2,16.51 36.2,25.4 35.56,26.04 v35.56,27.94
  Bottom 0.305: v35.56,27.94 35.56,28.57 35.81,28.83 35.81,37.72 41.27,43.18 41.27,50.42 JP1.1
IO9*  (via drill 0.5 pad 0.9)
  Top 0.254: U2.29 41.92,15.71 42.22,16.01 U1.29
  Top 0.305: U2.29 39.2,15.71 38.57,15.07 36.61,15.07 35.56,16.13 35.56,24.77 34.29,26.04 v34.29,26.67
  Bottom 0.305: v34.29,26.67 34.29,28.57 34.92,29.21 34.92,38.1 39.37,42.55 39.37,50.55 JP1.2
IO10*  (via drill 0.5 pad 0.9)
  Top 0.254: U1.30 42.51,15.51 41.91,14.91 U2.30
  Top 0.305: U2.30 39.67,14.91 39.04,14.28 36.27,14.28 34.92,15.62 34.92,24.13 33.02,26.04 v33.02,27.94
  Bottom 0.305: 36.58,50.16 36.58,49.78 36.83,49.53 | 36.58,50.16 JP1.3 | v33.02,27.94 33.02,28.57 34.04,29.59 34.04,38.48 36.83,41.27 36.83,49.91 36.58,50.16
IO11*  (via drill 0.5 pad 0.9)
  Top 0.254: U1.12 49.49,19.95 50.99,21.45 U2.12
  Top 0.305: U2.12 52.16,22.31 v52.07,22.23
  Bottom 0.305: v52.07,22.23 51.56,21.72 34.42,21.72 33.66,20.95 32.38,20.95 31.62,21.72 31.62,24.38 30.1,25.91 30.1,27.3 30.48,27.69 30.48,29.84 31.75,31.11 31.75,32.38 33.15,33.78 33.15,39.24 33.78,39.88 33.78,48.39 34.29,48.9 34.29,50.55 JP1.4
IO12  (via drill 0.5 pad 0.9)
  Top 0.254: U1.26 42.56,17.51 41.96,18.11 U2.26
  Top 0.305: U2.26 39.17,18.11 38.1,19.18 38.1,24.77 v38.73,25.4 | v33.02,31.75 v30.48,31.75
  Bottom 0.305: v38.73,25.4 33.91,25.4 31.75,27.56 31.75,29.21 33.02,30.48 v33.02,31.75 | JP1.5 31.5,49.78 32.89,48.39 32.89,41.02 32.26,40.39 32.26,34.16 30.48,32.38 v30.48,31.75
IO13*  (via drill 0.5 pad 0.9)
  Top 0.254: U1.32 43.09,14.51 41.88,13.31 U2.32
  Top 0.305: U2.32 40.36,13.31 39.73,12.68 35.59,12.68 33.66,14.61 33.66,22.86 33.02,23.5 31.75,23.5 29.21,26.04 v29.21,27.94 | IC2.3 21.28,33.73 v21.84,34.42
  Bottom 0.305: JP1.6 29.21,50.55 29.21,48.9 24.77,44.45 | v21.84,34.42 20.19,36.07 20.19,37.59 19.05,38.73 17.14,38.73 16.51,39.37 16.51,43.18 17.78,44.45 24.77,44.45 | v29.21,27.94 29.21,33.02 27.94,34.29 26.92,34.29 23.11,38.1 23.11,40.89 23.5,41.27 23.5,43.18 24.77,44.45
LL  (via drill 0.5 pad 0.9)
  Top 0.305: IC2.2 20.63,31.37 19.98,31.37 | 19.98,31.37 IC2.1 | v17.78,30.61 19.22,30.61 19.98,31.37 | RN2.2 14.21,24.36 14.61,24.77 14.61,26.04 13.97,26.67 10.16,26.67 9.53,27.3 v9.53,29.21
  Bottom 0.305: v17.78,30.61 16.51,29.21 v9.53,29.21
MISO
  Top 0.254: U1.11 50.45,19.01 51.97,20.52 U2.11
  Top 0.305: U2.11 52.79,21.04 54.61,22.86 59.31,22.86 60.96,24.51 60.96,26.04 62.23,27.3 62.23,28.57 63.63,29.97 ICSP.1
MOSI  (via drill 0.5 pad 0.9)
  Top 0.254: U1.10 50.79,18.51 51.97,19.68 U2.10
  Top 0.305: U2.10 54,19.71 v55.88,21.59
  Bottom 0.305: v55.88,21.59 56.52,21.59 61.59,26.67 64.77,26.67 ICSP.4
N$2
  Top 0.305: RN2.7 7.86,24.36 5.71,22.23 5.71,20.32 L.A
N$3
  Top 0.305: RN2.8 8.2,23.57 6.99,22.35 6.99,17.14 6.35,16.51 ON.A
N$6
  Top 0.305: RN2.6 6.5,25.16 5.5,24.16 TX.A
N$8
  Top 0.305: RN2.5 7.47,25.96 RX.A
RD+  (via drill 0.5 pad 0.9)
  Top 0.254: U2.4 52.02,14.91 51.42,15.51 U1.4
  Top 0.305: RN3.1 14.54,36.27 v14.61,36.2 | 58.98,14.78 v59.05,14.86 58.93,14.73 55.12,14.73 54.94,14.91 U2.4
  Bottom 0.305: v14.61,36.2 16.26,36.2 29.59,22.86 29.59,19.94 30.48,19.05 35.05,19.05 35.69,19.68 39.37,19.68 39.62,19.43 51.44,19.43 54.36,16.51 57.28,16.51 58.55,17.78 59.69,17.78 60.33,17.14 60.33,15.49 59.69,14.86 v59.05,14.86
RD-  (via drill 0.5 pad 0.9)
  Top 0.254: U1.3 51.18,15.01 52.08,14.11 U2.3
  Top 0.305: RN3.4 14.04,38.66 v14.61,38.1 | v59.05,13.34 58.28,14.11 U2.3
  Bottom 0.305: v14.61,38.1 15.37,38.1 30.23,23.24 30.23,20.57 31.11,19.68 34.67,19.68 35.31,20.32 40.01,20.32 40.26,20.19 51.69,20.19 54.48,17.4 57.15,17.4 58.17,18.41 60.33,18.41 60.96,17.78 60.96,14.61 59.69,13.34 v59.05,13.34
RESET  (via drill 0.5 pad 0.9)
  Top 0.254: U1.13 48.99,20.31 50.19,21.51 U2.13
  Top 0.305: v1.91,49.53 1.91,47.91 RESET.2 | v60.83,9.27 62.23,10.67 62.23,19.68 60.96,20.95 60.96,22.23 62.23,23.5 62.23,24.13 ICSP.5 64.9,26.67 64.9,30.99 64.14,31.75 62.87,31.75 61.59,30.48 61.59,27.94 60.33,26.67 60.33,26.37 D2.A 57.45,23.5 50.7,23.5 50.19,22.99 U2.13 | RN1.4 29.28,17.21 29.21,17.14 v29.21,14.61
  Top 0.61: RESET.2 4.92,47.15 5.08,46.99 8.26,46.99 8.42,47.15 RESET.1
  Bottom 0.305: J3.3 33.02,5.08 28.7,9.4 22.99,9.4 22.1,10.29 22.1,12.57 22.86,13.34 25.4,13.34 26.67,14.61 v29.21,14.61 | v1.91,49.53 1.27,48.9 1.27,44.45 3.05,42.67 3.05,39.5 3.81,38.73 3.81,37.47 3.05,36.7 3.05,33.53 0.89,31.37 0.89,27.18 1.4,26.67 17.78,26.67 20.07,24.38 20.07,23.75 v29.21,14.61 | v29.21,14.61 30.48,15.88 31.75,15.88 32.38,15.24 40.01,15.24 40.39,15.62 49.4,15.62 51.44,13.59 51.44,10.16 53.34,8.26 59.82,8.26 v60.83,9.27
RXLED  (via drill 0.5 pad 0.9)
  Top 0.254: U1.8 51.42,17.51 52.02,18.11 U2.8
  Top 0.305: v1.91,30.48 2.54,30.48 3.4,29.62 RX.C | U2.8 54.94,18.11 57.78,20.95 59.69,20.95 61.59,19.05 61.59,12.06 60.83,11.3 v60.83,10.79
  Bottom 0.305: v1.91,30.48 4.45,27.94 21.21,27.94 26.54,22.61 26.54,19.68 28.45,17.78 36.2,17.78 36.83,18.41 38.1,18.41 38.61,17.91 50.67,17.91 53.85,14.73 53.85,13.46 56.52,10.79 v60.83,10.79
SCK
  Top 0.254: U1.9 51.08,18.01 51.98,18.91 U2.9
  Top 0.305: U2.9 54.72,18.91 58.04,22.23 59.82,22.23 61.59,24 61.59,25.4 63.63,27.43 ICSP.3
TXLED  (via drill 0.5 pad 0.9)
  Top 0.254: 44.49,19.9 U1.22
  Top 0.279: U2.22 42.99,21.4 44.04,20.34 44.49,19.9
  Top 0.305: v1.91,28.57 1.91,24.77 2.54,24.13 TX.C | 44.04,20.34 44.19,20.2 | U2.22 42.99,24.07 41.27,25.78 41.27,26.67 41.91,27.3 41.91,28.57 41.27,29.21 28.57,29.21 v23.5,24.13
  Bottom 0.305: v1.91,28.57 3.17,27.3 20.32,27.3 v23.5,24.13
UCAP
  Top 0.254: U1.6 U2.6
  Top 0.406: U2.6 C7.1
UGND  (via drill 0.5 pad 0.9)
  Top 0.254: U2.5 52.01,15.71 51.71,16.01 U1.5
  Top 0.406: L2.1 11.43,32.38 v10.16,33.66 8.89,34.92 8.89,35.56 7.67,36.78 J1.P5 | v59.05,16.51 C7.2 57.78,16.5 57.78,15.49 55.5,15.49 55.28,15.71 U2.5
  Bottom 0.406: v10.16,33.66 17.78,33.66 28.83,22.61 28.83,19.43 29.84,18.41 35.56,18.41 36.2,19.05 38.73,19.05 39.12,18.67 51.05,18.67 53.85,15.88 55.62,15.88 R3.2 55.88,15.88 58.42,15.88 v59.05,16.51
VIN  (via drill 0.5 pad 0.9)
  Top 0.305: RN1.1 29.53,19.61 29.46,19.68 29.46,20.95 28.7,21.72 20.7,21.72 v19.68,20.7
  Top 0.406: v19.68,20.7 19.68,19.53 IC1.3
  Top 0.813: IC1.3 19.61,20.88 v19.68,20.7 | v24.13,11.43 22.86,11.43 21.59,10.16 D1.C
  Top 1.016: EXTPOWER.2 12.48,9.11 13.74,9.12 C10.+ | C10.+ 17.21,9.12 | D1.C 18.48,9.82 C10.+
  Bottom 0.813: v19.68,20.7 19.68,11.43 18.41,10.16 13.54,10.16 EXTPOWER.2 | J3.8 45.72,3.81 43.18,6.35 34.92,6.35 29.84,11.43 v24.13,11.43
VUSB  (via drill 0.5 pad 0.9)
  Top 0.254: U1.7 51.73,17.01 52.03,17.31 U2.7
  Top 0.305: 56.52,17.8 C9.2
  Top 0.406: 56.52,18.41 56.52,17.8 | 56.52,18.41 57.78,19.68 v59.05,19.68 | U2.7 55.41,17.31 56.52,18.41 | 56.52,18.41 C9.2 | R4.2 17.78,38.35
  Top 0.61: F1.1 15.29,42.5 v17.78,40.01 17.78,38.35 17.78,34.92 15.88,33.02 15.88,30.48 14.84,29.44 C8.+ 14.86,28.55 T1.1
  Bottom 0.406: v59.05,19.68 58.42,19.05 57.78,19.05 56.9,18.16 54.86,18.16 52.07,20.95 34.8,20.95 34.16,20.32 31.75,20.32 30.86,21.21 30.86,23.75 26.04,28.57 26.04,31.75 20.95,36.83 20.95,38.1 19.05,40.01 v17.78,40.01
XTAL1
  Top 0.254: U1.17 U2.17
  Top 0.305: U2.17 46.99,24.75 R1.1 47.62,25.4 46.99,26.04 46.99,29.21 47.51,29.73 Y1.1 47.97,30.84 C4.1
XTAL2
  Top 0.254: U1.16 47.49,21.15 47.79,21.45 U2.16
  Top 0.305: U2.16 47.79,24.28 R1.2 49.55,25.8 49.55,27.15 Y1.3 49.82,27.56 C3.2
XUSB  (via drill 0.5 pad 0.9)
  Top 0.406: J1.P1 7.67,39.42 9.12,40.88 | 9.12,40.88 10.79,42.55 | v9.6,40.3 9.5,40.4 9.5,40.5 9.12,40.88
  Top 0.61: 10.79,42.55 10.79,43.23 F1.2
  Bottom 0.406: VUSB.X 9.63,36.83 10.2,37.4 10.2,39.7 v9.6,40.3

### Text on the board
Bottom: 2017-REV3d
tPlace: PWM COMPL1 | PWM COMPL2 | 13 | 12 | 11 | 10 | 9 | 8 | 7 | 6 | 5 | 4 | 3 | 2 | 1 | 0 | -
tNames: SCL | SDA | A11 | A10 | A9 | A8 | (AIN0) | A7 | A6 | # | # | # | # | GND | # | # | # | AREF | DIGITAL | [#=PWM] | TX1 | RX1 | TM | Arduino | LEONARDO | www.arduino.cc | 1 | ANALOG IN | IOREF | RST | 3V3 | 5V | GND | GND | VIN | A0 | A1 | A2 | A3 | A4 | A5
bNames: MADE IN | ITALY
ReferenceLC: X2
